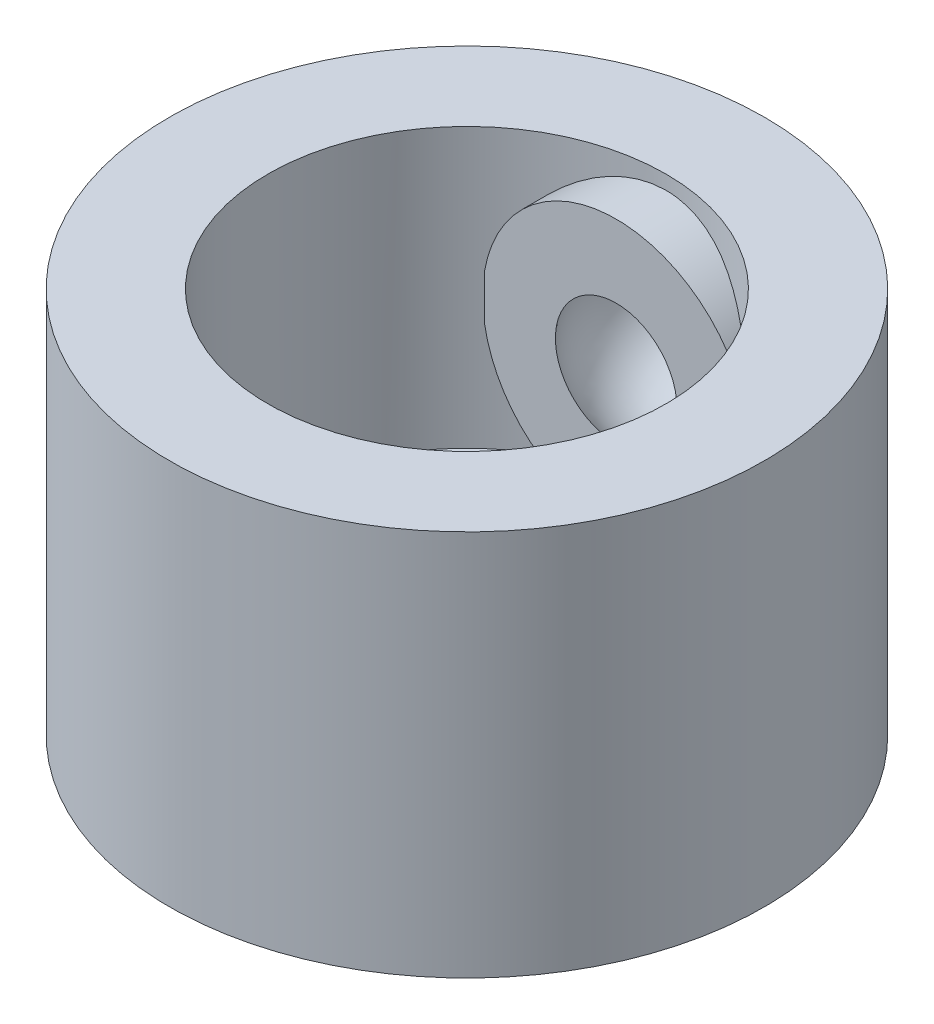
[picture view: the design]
ISO-10303-21;
HEADER;
FILE_DESCRIPTION(('STEP AP214'),'2;1');
FILE_NAME('part.step','',(''),(''),'','','');
FILE_SCHEMA(('AUTOMOTIVE_DESIGN { 1 0 10303 214 1 1 1 1 }'));
ENDSEC;
DATA;
#1=APPLICATION_CONTEXT('core data for automotive mechanical design processes');
#2=APPLICATION_PROTOCOL_DEFINITION('international standard','automotive_design',2000,#1);
#3=PRODUCT_CONTEXT('',#1,'mechanical');
#4=PRODUCT('Part','Part','',(#3));
#5=PRODUCT_RELATED_PRODUCT_CATEGORY('part','',(#4));
#6=PRODUCT_DEFINITION_FORMATION('','',#4);
#7=PRODUCT_DEFINITION_CONTEXT('part definition',#1,'design');
#8=PRODUCT_DEFINITION('design','',#6,#7);
#9=PRODUCT_DEFINITION_SHAPE('','',#8);
#10=(LENGTH_UNIT() NAMED_UNIT(*) SI_UNIT(.MILLI.,.METRE.));
#11=(NAMED_UNIT(*) PLANE_ANGLE_UNIT() SI_UNIT($,.RADIAN.));
#12=(NAMED_UNIT(*) SI_UNIT($,.STERADIAN.) SOLID_ANGLE_UNIT());
#13=UNCERTAINTY_MEASURE_WITH_UNIT(LENGTH_MEASURE(1.E-05),#10,'distance_accuracy_value','');
#14=(GEOMETRIC_REPRESENTATION_CONTEXT(3) GLOBAL_UNCERTAINTY_ASSIGNED_CONTEXT((#13)) GLOBAL_UNIT_ASSIGNED_CONTEXT((#10,
#11,#12)) REPRESENTATION_CONTEXT('',''));
#15=CARTESIAN_POINT('',(0.,0.,0.));
#16=DIRECTION('',(0.,0.,1.));
#17=DIRECTION('',(1.,0.,0.));
#18=AXIS2_PLACEMENT_3D('',#15,#16,#17);
#19=CARTESIAN_POINT('',(0.,0.,0.));
#20=DIRECTION('',(0.,-1.,0.));
#21=DIRECTION('',(0.,0.,-1.));
#22=AXIS2_PLACEMENT_3D('',#19,#20,#21);
#23=CYLINDRICAL_SURFACE('',#22,9.5);
#24=CARTESIAN_POINT('',(0.,19.1,0.));
#25=DIRECTION('',(0.,-1.,0.));
#26=DIRECTION('',(0.,0.,-1.));
#27=AXIS2_PLACEMENT_3D('',#24,#25,#26);
#28=CIRCLE('',#27,9.5);
#29=CARTESIAN_POINT('',(0.,19.1,-9.5));
#30=VERTEX_POINT('',#29);
#31=EDGE_CURVE('E335',#30,#30,#28,.T.);
#32=ORIENTED_EDGE('',*,*,#31,.F.);
#33=EDGE_LOOP('',(#32));
#34=FACE_BOUND('',#33,.T.);
#35=CARTESIAN_POINT('',(0.,18.426793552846,-9.5));
#36=CARTESIAN_POINT('',(-0.159955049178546,18.4268000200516,-9.50000608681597));
#37=CARTESIAN_POINT('',(-0.319855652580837,18.42077115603,-9.49595483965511));
#38=CARTESIAN_POINT('',(-0.638400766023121,18.3967651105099,-9.47986515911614));
#39=CARTESIAN_POINT('',(-0.797045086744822,18.3787861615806,-9.46782554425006));
#40=CARTESIAN_POINT('',(-1.11185658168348,18.3311336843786,-9.43603899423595));
#41=CARTESIAN_POINT('',(-1.26802238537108,18.3014539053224,-9.41628793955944));
#42=CARTESIAN_POINT('',(-1.57673369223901,18.2308164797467,-9.36954083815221));
#43=CARTESIAN_POINT('',(-1.7292776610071,18.1898541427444,-9.34254177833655));
#44=CARTESIAN_POINT('',(-2.02889611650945,18.0974390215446,-9.28206910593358));
#45=CARTESIAN_POINT('',(-2.17599564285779,18.0460439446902,-9.24863115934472));
#46=CARTESIAN_POINT('',(-2.46481833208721,17.9332165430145,-9.17588635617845));
#47=CARTESIAN_POINT('',(-2.60653937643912,17.8717803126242,-9.13657721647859));
#48=CARTESIAN_POINT('',(-3.02249175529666,17.6733685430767,-9.01100542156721));
#49=CARTESIAN_POINT('',(-3.28778948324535,17.5222030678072,-8.91704027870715));
#50=CARTESIAN_POINT('',(-3.81192368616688,17.1725484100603,-8.70665509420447));
#51=CARTESIAN_POINT('',(-4.06827356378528,16.9711202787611,-8.58900271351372));
#52=CARTESIAN_POINT('',(-4.54601008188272,16.5335648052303,-8.34599410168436));
#53=CARTESIAN_POINT('',(-4.76734517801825,16.2973872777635,-8.22062688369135));
#54=CARTESIAN_POINT('',(-5.08723094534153,15.8995079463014,-8.02428499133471));
#55=CARTESIAN_POINT('',(-5.19834388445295,15.748116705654,-7.95255091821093));
#56=CARTESIAN_POINT('',(-5.40733945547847,15.4352063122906,-7.81194973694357));
#57=CARTESIAN_POINT('',(-5.50521902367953,15.2736848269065,-7.74308329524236));
#58=CARTESIAN_POINT('',(-5.77765072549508,14.7749551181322,-7.54446686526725));
#59=CARTESIAN_POINT('',(-5.93164679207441,14.4227774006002,-7.42227988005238));
#60=CARTESIAN_POINT('',(-6.1400691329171,13.793123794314,-7.24999268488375));
#61=CARTESIAN_POINT('',(-6.21043874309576,13.5238532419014,-7.18926134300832));
#62=CARTESIAN_POINT('',(-6.28938905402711,13.1114611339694,-7.12002436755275));
#63=CARTESIAN_POINT('',(-6.31126834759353,12.9726402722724,-7.10059214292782));
#64=CARTESIAN_POINT('',(-6.34586023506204,12.6929523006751,-7.06969705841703));
#65=CARTESIAN_POINT('',(-6.35857278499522,12.552085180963,-7.05823423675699));
#66=CARTESIAN_POINT('',(-6.37462651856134,12.2687615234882,-7.04373851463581));
#67=CARTESIAN_POINT('',(-6.37792636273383,12.126300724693,-7.04074280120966));
#68=CARTESIAN_POINT('',(-6.37497619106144,11.8415610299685,-7.04341413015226));
#69=CARTESIAN_POINT('',(-6.36872615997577,11.6992821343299,-7.04908118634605));
#70=CARTESIAN_POINT('',(-6.34678750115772,11.4159862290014,-7.06884048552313));
#71=CARTESIAN_POINT('',(-6.33109488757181,11.2749697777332,-7.0829362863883));
#72=CARTESIAN_POINT('',(-6.29054894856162,10.9952512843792,-7.11896875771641));
#73=CARTESIAN_POINT('',(-6.26569167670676,10.8565502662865,-7.14090880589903));
#74=CARTESIAN_POINT('',(-6.18071239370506,10.4583149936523,-7.21486763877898));
#75=CARTESIAN_POINT('',(-6.10902315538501,10.2028738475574,-7.27614949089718));
#76=CARTESIAN_POINT('',(-5.93675463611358,9.70746962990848,-7.41736054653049));
#77=CARTESIAN_POINT('',(-5.83615321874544,9.46751859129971,-7.49730402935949));
#78=CARTESIAN_POINT('',(-5.63877532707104,9.06609767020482,-7.64625597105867));
#79=CARTESIAN_POINT('',(-5.54799125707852,8.90062327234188,-7.71258545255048));
#80=CARTESIAN_POINT('',(-5.35298805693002,8.57951010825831,-7.84918340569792));
#81=CARTESIAN_POINT('',(-5.24876897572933,8.42387130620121,-7.91945186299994));
#82=CARTESIAN_POINT('',(-5.02731949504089,8.12258714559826,-8.06184989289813));
#83=CARTESIAN_POINT('',(-4.91006633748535,7.97696000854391,-8.13398254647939));
#84=CARTESIAN_POINT('',(-4.66318956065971,7.69648935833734,-8.27798782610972));
#85=CARTESIAN_POINT('',(-4.53356733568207,7.56164463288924,-8.34986048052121));
#86=CARTESIAN_POINT('',(-4.26131477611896,7.30233702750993,-8.49205301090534));
#87=CARTESIAN_POINT('',(-4.1185914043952,7.17796271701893,-8.56235653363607));
#88=CARTESIAN_POINT('',(-3.82148500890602,6.94159788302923,-8.69902193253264));
#89=CARTESIAN_POINT('',(-3.66710343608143,6.82960582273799,-8.76538429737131));
#90=CARTESIAN_POINT('',(-3.34752961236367,6.61915446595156,-8.89233138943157));
#91=CARTESIAN_POINT('',(-3.18235579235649,6.52067294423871,-8.95292555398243));
#92=CARTESIAN_POINT('',(-2.84181045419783,6.33817920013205,-9.06676981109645));
#93=CARTESIAN_POINT('',(-2.66644201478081,6.25416263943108,-9.12002210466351));
#94=CARTESIAN_POINT('',(-2.34642263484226,6.11864547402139,-9.20681271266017));
#95=CARTESIAN_POINT('',(-2.20354559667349,6.0640620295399,-9.24210714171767));
#96=CARTESIAN_POINT('',(-1.9130077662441,5.9649822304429,-9.30658522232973));
#97=CARTESIAN_POINT('',(-1.765347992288,5.92048374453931,-9.33577016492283));
#98=CARTESIAN_POINT('',(-1.46614983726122,5.84211758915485,-9.38740856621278));
#99=CARTESIAN_POINT('',(-1.31461330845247,5.80824494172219,-9.40986517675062));
#100=CARTESIAN_POINT('',(-1.0085905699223,5.75155139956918,-9.44756634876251));
#101=CARTESIAN_POINT('',(-0.854104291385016,5.72873076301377,-9.46281074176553));
#102=CARTESIAN_POINT('',(-0.542824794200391,5.69441736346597,-9.48576676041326));
#103=CARTESIAN_POINT('',(-0.386025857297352,5.68296037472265,-9.49345459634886));
#104=CARTESIAN_POINT('',(-0.0718204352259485,5.67167337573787,-9.50102820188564));
#105=CARTESIAN_POINT('',(0.0855860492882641,5.67184335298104,-9.50091397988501));
#106=CARTESIAN_POINT('',(0.399766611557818,5.68380821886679,-9.49288587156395));
#107=CARTESIAN_POINT('',(0.55654064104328,5.6956039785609,-9.48497140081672));
#108=CARTESIAN_POINT('',(0.868220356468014,5.73064203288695,-9.4615337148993));
#109=CARTESIAN_POINT('',(1.02312607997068,5.75388409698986,-9.44601065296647));
#110=CARTESIAN_POINT('',(1.32249964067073,5.81008456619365,-9.40864650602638));
#111=CARTESIAN_POINT('',(1.4671094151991,5.84251725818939,-9.38714822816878));
#112=CARTESIAN_POINT('',(1.75277263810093,5.91704743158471,-9.33803159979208));
#113=CARTESIAN_POINT('',(1.89382484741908,5.95914823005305,-9.31041114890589));
#114=CARTESIAN_POINT('',(2.31039010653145,6.09926368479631,-9.21914737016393));
#115=CARTESIAN_POINT('',(2.57954474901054,6.2111359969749,-9.14707131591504));
#116=CARTESIAN_POINT('',(3.11756982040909,6.478452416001,-8.97869592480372));
#117=CARTESIAN_POINT('',(3.38450501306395,6.63677381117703,-8.88086716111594));
#118=CARTESIAN_POINT('',(3.88943647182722,6.98736062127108,-8.67161913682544));
#119=CARTESIAN_POINT('',(4.12740873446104,7.17965387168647,-8.56018875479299));
#120=CARTESIAN_POINT('',(4.47910671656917,7.50770014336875,-8.37907493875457));
#121=CARTESIAN_POINT('',(4.60325926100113,7.63358824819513,-8.31136176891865));
#122=CARTESIAN_POINT('',(4.84062795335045,7.89512373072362,-8.17539031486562));
#123=CARTESIAN_POINT('',(4.95384145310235,8.03077345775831,-8.1071319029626));
#124=CARTESIAN_POINT('',(5.1689032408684,8.31139025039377,-7.97173745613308));
#125=CARTESIAN_POINT('',(5.27074821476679,8.45636001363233,-7.90460175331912));
#126=CARTESIAN_POINT('',(5.46254982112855,8.75522236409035,-7.7732907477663));
#127=CARTESIAN_POINT('',(5.55250856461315,8.90911335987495,-7.70911492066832));
#128=CARTESIAN_POINT('',(5.70698393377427,9.20101374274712,-7.5952662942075));
#129=CARTESIAN_POINT('',(5.77328407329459,9.3378040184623,-7.54488456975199));
#130=CARTESIAN_POINT('',(5.89648305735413,9.61724513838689,-7.44899868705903));
#131=CARTESIAN_POINT('',(5.95338126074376,9.75989638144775,-7.40349486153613));
#132=CARTESIAN_POINT('',(6.05713350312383,10.0504044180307,-7.31885329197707));
#133=CARTESIAN_POINT('',(6.104002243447,10.1982532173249,-7.27970625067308));
#134=CARTESIAN_POINT('',(6.18716664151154,10.4986376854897,-7.20915731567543));
#135=CARTESIAN_POINT('',(6.22346848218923,10.6511705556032,-7.17775089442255));
#136=CARTESIAN_POINT('',(6.28035686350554,10.9370806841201,-7.12799581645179));
#137=CARTESIAN_POINT('',(6.30247703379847,11.0699364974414,-7.10840032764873));
#138=CARTESIAN_POINT('',(6.33831117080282,11.3375926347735,-7.07646743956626));
#139=CARTESIAN_POINT('',(6.35202902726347,11.4723920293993,-7.06412668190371));
#140=CARTESIAN_POINT('',(6.37084376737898,11.7430222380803,-7.04716340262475));
#141=CARTESIAN_POINT('',(6.3759443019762,11.8788525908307,-7.04253761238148));
#142=CARTESIAN_POINT('',(6.37744770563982,12.150604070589,-7.04117611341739));
#143=CARTESIAN_POINT('',(6.37385036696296,12.2865251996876,-7.04444059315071));
#144=CARTESIAN_POINT('',(6.3580301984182,12.5572498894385,-7.05872278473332));
#145=CARTESIAN_POINT('',(6.34582019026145,12.6920548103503,-7.06972897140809));
#146=CARTESIAN_POINT('',(6.3129938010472,12.9598512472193,-7.09905461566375));
#147=CARTESIAN_POINT('',(6.29237457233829,13.0928421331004,-7.11737655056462));
#148=CARTESIAN_POINT('',(6.21830463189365,13.4880400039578,-7.18241685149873));
#149=CARTESIAN_POINT('',(6.15264722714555,13.7463818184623,-7.23920425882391));
#150=CARTESIAN_POINT('',(5.96500601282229,14.3315860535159,-7.3951236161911));
#151=CARTESIAN_POINT('',(5.831551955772,14.6526657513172,-7.50205712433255));
#152=CARTESIAN_POINT('',(5.5969492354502,15.1105905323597,-7.67683255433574));
#153=CARTESIAN_POINT('',(5.51289618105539,15.2594386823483,-7.73756414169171));
#154=CARTESIAN_POINT('',(5.33377037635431,15.549049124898,-7.86210972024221));
#155=CARTESIAN_POINT('',(5.23869841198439,15.6898119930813,-7.9259234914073));
#156=CARTESIAN_POINT('',(5.03618350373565,15.9653713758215,-8.05615417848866));
#157=CARTESIAN_POINT('',(4.92854673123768,16.1000124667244,-8.12259733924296));
#158=CARTESIAN_POINT('',(4.70268570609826,16.3602115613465,-8.25541724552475));
#159=CARTESIAN_POINT('',(4.584458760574,16.4857672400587,-8.32179396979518));
#160=CARTESIAN_POINT('',(4.33776545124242,16.7272947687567,-8.45300603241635));
#161=CARTESIAN_POINT('',(4.20929814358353,16.8432657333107,-8.51784122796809));
#162=CARTESIAN_POINT('',(3.94246774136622,17.0650316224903,-8.64458030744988));
#163=CARTESIAN_POINT('',(3.80410326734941,17.1708251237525,-8.70648378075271));
#164=CARTESIAN_POINT('',(3.50321674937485,17.3818002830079,-8.83214002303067));
#165=CARTESIAN_POINT('',(3.33967248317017,17.485806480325,-8.89543136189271));
#166=CARTESIAN_POINT('',(3.00192120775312,17.679371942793,-9.01501780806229));
#167=CARTESIAN_POINT('',(2.82771964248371,17.7689385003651,-9.07131644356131));
#168=CARTESIAN_POINT('',(2.46993175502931,17.9323059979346,-9.17518705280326));
#169=CARTESIAN_POINT('',(2.2863620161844,18.0061336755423,-9.2227738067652));
#170=CARTESIAN_POINT('',(1.91113844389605,18.1369130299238,-9.30776827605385));
#171=CARTESIAN_POINT('',(1.71948893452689,18.1938736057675,-9.34518135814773));
#172=CARTESIAN_POINT('',(1.27751182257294,18.302691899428,-9.41703452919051));
#173=CARTESIAN_POINT('',(1.0252324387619,18.3490837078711,-9.44798604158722));
#174=CARTESIAN_POINT('',(0.515253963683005,18.4111250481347,-9.48946103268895));
#175=CARTESIAN_POINT('',(0.257556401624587,18.4267831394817,-9.49999019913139));
#176=CARTESIAN_POINT('',(0.,18.426793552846,-9.5));
#177=B_SPLINE_CURVE_WITH_KNOTS('',3,(#35,#36,#37,#38,#39,#40,#41,#42,#43,#44,#45,#46,#47,#48,
#49,#50,#51,#52,#53,#54,#55,#56,#57,#58,#59,#60,#61,#62,#63,#64,#65,#66,#67,#68,#69,#70,#71,#72,
#73,#74,#75,#76,#77,#78,#79,#80,#81,#82,#83,#84,#85,#86,#87,#88,#89,#90,#91,#92,#93,#94,#95,#96,
#97,#98,#99,#100,#101,#102,#103,#104,#105,#106,#107,#108,#109,#110,#111,#112,#113,#114,#115,
#116,#117,#118,#119,#120,#121,#122,#123,#124,#125,#126,#127,#128,#129,#130,#131,#132,#133,#134,
#135,#136,#137,#138,#139,#140,#141,#142,#143,#144,#145,#146,#147,#148,#149,#150,#151,#152,#153,
#154,#155,#156,#157,#158,#159,#160,#161,#162,#163,#164,#165,#166,#167,#168,#169,#170,#171,#172,
#173,#174,#175,#176),.UNSPECIFIED.,.T.,.F.,(4,2,2,2,2,2,2,2,2,2,2,2,2,2,2,2,2,2,2,2,2,2,2,2,2,2,
2,2,2,2,2,2,2,2,2,2,2,2,2,2,2,2,2,2,2,2,2,2,2,2,2,2,2,2,2,2,2,2,2,2,2,2,2,2,2,2,2,2,2,2,4),(0.,
0.479607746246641,0.95928644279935,1.43922173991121,1.91935686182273,2.39690520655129,
2.8746397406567,3.82923005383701,4.8653414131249,5.90296409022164,6.50538335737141,
7.1079418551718,8.30975029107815,9.16072070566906,9.58586396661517,10.0110092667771,
10.4380188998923,10.8650292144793,11.2922199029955,11.7195947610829,12.5332430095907,
13.3475158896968,13.9469748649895,14.5464316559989,15.1469520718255,15.7474048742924,
16.3525117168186,16.9575433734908,17.5615674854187,18.1654101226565,18.6358383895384,
19.1061671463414,19.5762752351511,20.046394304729,20.5179887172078,20.9895826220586,
21.4612118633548,21.9328316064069,22.38158569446,22.8304939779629,23.7276011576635,
24.7003056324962,25.6738108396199,26.241322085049,26.8089703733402,27.3767837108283,
27.9444960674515,28.4245075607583,28.9045517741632,29.3838874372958,29.862942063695,
30.270813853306,30.6784966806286,31.0860067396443,31.4935265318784,31.9004409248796,
32.3074932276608,33.1218666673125,34.2070549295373,34.750886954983,35.2946802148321,
35.8483807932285,36.4022225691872,36.9561154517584,37.510085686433,38.1208690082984,
38.7313428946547,39.3407712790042,39.9498775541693,40.7223474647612,41.4946022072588),.UNSPECIFIED.);
#178=CARTESIAN_POINT('',(-6.2850694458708,10.9723181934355,-7.12375617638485));
#179=VERTEX_POINT('',#178);
#180=CARTESIAN_POINT('',(-1.26530471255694,5.8,-9.41536000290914));
#181=VERTEX_POINT('',#180);
#182=EDGE_CURVE('E245',#179,#181,#177,.T.);
#183=ORIENTED_EDGE('',*,*,#182,.F.);
#184=DIRECTION('',(0.,-1.,0.));
#185=VECTOR('',#184,1.);
#186=CARTESIAN_POINT('',(-6.2850694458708,0.,-7.12375617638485));
#187=LINE('',#186,#185);
#188=CARTESIAN_POINT('',(-6.2850694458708,13.1276818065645,-7.12375617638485));
#189=VERTEX_POINT('',#188);
#190=EDGE_CURVE('E247',#189,#179,#187,.T.);
#191=ORIENTED_EDGE('',*,*,#190,.F.);
#192=CARTESIAN_POINT('',(6.2850694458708,13.1276818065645,-7.12375617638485));
#193=VERTEX_POINT('',#192);
#194=EDGE_CURVE('E246',#193,#189,#177,.T.);
#195=ORIENTED_EDGE('',*,*,#194,.F.);
#196=DIRECTION('',(0.,-1.,0.));
#197=VECTOR('',#196,1.);
#198=CARTESIAN_POINT('',(6.2850694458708,0.,-7.12375617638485));
#199=LINE('',#198,#197);
#200=CARTESIAN_POINT('',(6.2850694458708,10.9723181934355,-7.12375617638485));
#201=VERTEX_POINT('',#200);
#202=EDGE_CURVE('E287',#201,#193,#199,.F.);
#203=ORIENTED_EDGE('',*,*,#202,.F.);
#204=CARTESIAN_POINT('',(1.26530471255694,5.8,-9.41536000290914));
#205=VERTEX_POINT('',#204);
#206=EDGE_CURVE('E236',#205,#201,#177,.T.);
#207=ORIENTED_EDGE('',*,*,#206,.F.);
#208=CARTESIAN_POINT('',(0.,5.8,0.));
#209=DIRECTION('',(0.,-1.,0.));
#210=DIRECTION('',(0.,0.,-1.));
#211=AXIS2_PLACEMENT_3D('',#208,#209,#210);
#212=CIRCLE('',#211,9.5);
#213=EDGE_CURVE('E286',#205,#181,#212,.T.);
#214=ORIENTED_EDGE('',*,*,#213,.T.);
#215=EDGE_LOOP('',(#183,#191,#195,#203,#207,#214));
#216=FACE_BOUND('',#215,.T.);
#217=ADVANCED_FACE('F52',(#34,#216),#23,.F.);
#218=CARTESIAN_POINT('',(-9.5,5.8,0.));
#219=DIRECTION('',(0.,-1.,0.));
#220=DIRECTION('',(0.,0.,-1.));
#221=AXIS2_PLACEMENT_3D('',#218,#219,#220);
#222=PLANE('',#221);
#223=DIRECTION('',(-1.,0.,0.));
#224=VECTOR('',#223,1.);
#225=CARTESIAN_POINT('',(-9.5,5.8,3.175));
#226=LINE('',#225,#224);
#227=CARTESIAN_POINT('',(1.83308710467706,5.8,3.175));
#228=VERTEX_POINT('',#227);
#229=CARTESIAN_POINT('',(-1.83308710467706,5.8,3.175));
#230=VERTEX_POINT('',#229);
#231=EDGE_CURVE('E214',#228,#230,#226,.T.);
#232=ORIENTED_EDGE('',*,*,#231,.T.);
#233=DIRECTION('',(-0.5,0.,-0.866025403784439));
#234=VECTOR('',#233,1.);
#235=CARTESIAN_POINT('',(-5.12463065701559,5.8,-2.52612066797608));
#236=LINE('',#235,#234);
#237=CARTESIAN_POINT('',(-3.66617420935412,5.8,0.));
#238=VERTEX_POINT('',#237);
#239=EDGE_CURVE('E218',#230,#238,#236,.T.);
#240=ORIENTED_EDGE('',*,*,#239,.T.);
#241=DIRECTION('',(0.5,0.,-0.866025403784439));
#242=VECTOR('',#241,1.);
#243=CARTESIAN_POINT('',(-5.12463065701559,5.8,2.52612066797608));
#244=LINE('',#243,#242);
#245=CARTESIAN_POINT('',(-1.83308710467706,5.8,-3.175));
#246=VERTEX_POINT('',#245);
#247=EDGE_CURVE('E203',#238,#246,#244,.T.);
#248=ORIENTED_EDGE('',*,*,#247,.T.);
#249=DIRECTION('',(1.,0.,0.));
#250=VECTOR('',#249,1.);
#251=CARTESIAN_POINT('',(-9.5,5.8,-3.175));
#252=LINE('',#251,#250);
#253=CARTESIAN_POINT('',(1.83308710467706,5.8,-3.175));
#254=VERTEX_POINT('',#253);
#255=EDGE_CURVE('E156',#246,#254,#252,.T.);
#256=ORIENTED_EDGE('',*,*,#255,.T.);
#257=DIRECTION('',(0.5,0.,0.866025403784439));
#258=VECTOR('',#257,1.);
#259=CARTESIAN_POINT('',(0.374630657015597,5.8,-5.70112066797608));
#260=LINE('',#259,#258);
#261=CARTESIAN_POINT('',(3.66617420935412,5.8,0.));
#262=VERTEX_POINT('',#261);
#263=EDGE_CURVE('E206',#254,#262,#260,.T.);
#264=ORIENTED_EDGE('',*,*,#263,.T.);
#265=DIRECTION('',(-0.5,0.,0.866025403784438));
#266=VECTOR('',#265,1.);
#267=CARTESIAN_POINT('',(0.37463065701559,5.8,5.70112066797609));
#268=LINE('',#267,#266);
#269=EDGE_CURVE('E210',#262,#228,#268,.T.);
#270=ORIENTED_EDGE('',*,*,#269,.T.);
#271=EDGE_LOOP('',(#232,#240,#248,#256,#264,#270));
#272=FACE_BOUND('',#271,.T.);
#273=DIRECTION('',(0.,0.,-1.));
#274=VECTOR('',#273,1.);
#275=CARTESIAN_POINT('',(-1.26530471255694,5.8,-13.8));
#276=LINE('',#275,#274);
#277=CARTESIAN_POINT('',(-1.26530471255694,5.8,-7.12375617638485));
#278=VERTEX_POINT('',#277);
#279=EDGE_CURVE('E62',#181,#278,#276,.F.);
#280=ORIENTED_EDGE('',*,*,#279,.F.);
#281=ORIENTED_EDGE('',*,*,#213,.F.);
#282=DIRECTION('',(0.,0.,-1.));
#283=VECTOR('',#282,1.);
#284=CARTESIAN_POINT('',(1.26530471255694,5.8,-13.8));
#285=LINE('',#284,#283);
#286=CARTESIAN_POINT('',(1.26530471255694,5.8,-7.12375617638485));
#287=VERTEX_POINT('',#286);
#288=EDGE_CURVE('E361',#287,#205,#285,.T.);
#289=ORIENTED_EDGE('',*,*,#288,.F.);
#290=DIRECTION('',(1.,0.,0.));
#291=VECTOR('',#290,1.);
#292=CARTESIAN_POINT('',(-9.5,5.8,-7.12375617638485));
#293=LINE('',#292,#291);
#294=EDGE_CURVE('E362',#278,#287,#293,.T.);
#295=ORIENTED_EDGE('',*,*,#294,.F.);
#296=EDGE_LOOP('',(#280,#281,#289,#295));
#297=FACE_BOUND('',#296,.T.);
#298=ADVANCED_FACE('F275',(#272,#297),#222,.F.);
#299=CARTESIAN_POINT('',(0.,12.05,-14.2));
#300=DIRECTION('',(0.,0.,1.));
#301=DIRECTION('',(1.,0.,0.));
#302=AXIS2_PLACEMENT_3D('',#299,#300,#301);
#303=CYLINDRICAL_SURFACE('',#302,5.75);
#304=CARTESIAN_POINT('',(0.,17.8,-14.2));
#305=CARTESIAN_POINT('',(-0.154438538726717,17.7999990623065,-14.1999992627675));
#306=CARTESIAN_POINT('',(-0.308934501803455,17.7937693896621,-14.1974735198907));
#307=CARTESIAN_POINT('',(-0.616831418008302,17.7689073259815,-14.1874336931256));
#308=CARTESIAN_POINT('',(-0.770231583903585,17.7502667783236,-14.1799163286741));
#309=CARTESIAN_POINT('',(-1.07506274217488,17.7007194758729,-14.1600711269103));
#310=CARTESIAN_POINT('',(-1.22648886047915,17.6697867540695,-14.1477331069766));
#311=CARTESIAN_POINT('',(-1.52601131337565,17.5959529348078,-14.118567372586));
#312=CARTESIAN_POINT('',(-1.67410626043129,17.5530469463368,-14.1017378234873));
#313=CARTESIAN_POINT('',(-1.96536366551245,17.4558603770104,-14.0640971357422));
#314=CARTESIAN_POINT('',(-2.10854251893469,17.4016229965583,-14.0433011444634));
#315=CARTESIAN_POINT('',(-2.38970684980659,17.2821264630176,-13.9981993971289));
#316=CARTESIAN_POINT('',(-2.52769036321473,17.216863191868,-13.9738923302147));
#317=CARTESIAN_POINT('',(-2.79751487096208,17.075888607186,-13.9223832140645));
#318=CARTESIAN_POINT('',(-2.92936045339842,17.0001852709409,-13.8951833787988));
#319=CARTESIAN_POINT('',(-3.18632520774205,16.8388284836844,-13.8385215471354));
#320=CARTESIAN_POINT('',(-3.31144191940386,16.7531714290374,-13.8090587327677));
#321=CARTESIAN_POINT('',(-3.68623328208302,16.4742305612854,-13.715672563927));
#322=CARTESIAN_POINT('',(-3.92367604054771,16.2650555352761,-13.6490612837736));
#323=CARTESIAN_POINT('',(-4.36119743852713,15.810586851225,-13.5156377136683));
#324=CARTESIAN_POINT('',(-4.56125739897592,15.5652752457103,-13.4488253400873));
#325=CARTESIAN_POINT('',(-4.83372214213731,15.1684976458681,-13.3523408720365));
#326=CARTESIAN_POINT('',(-4.92153257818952,15.0280082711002,-13.320140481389));
#327=CARTESIAN_POINT('',(-5.08492368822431,14.7395161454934,-13.2586261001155));
#328=CARTESIAN_POINT('',(-5.16050940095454,14.5915165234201,-13.2293109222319));
#329=CARTESIAN_POINT('',(-5.29880999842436,14.2889267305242,-13.174526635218));
#330=CARTESIAN_POINT('',(-5.36152410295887,14.1343361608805,-13.1490577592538));
#331=CARTESIAN_POINT('',(-5.47343031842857,13.8197217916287,-13.1028709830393));
#332=CARTESIAN_POINT('',(-5.52262925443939,13.6597007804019,-13.082150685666));
#333=CARTESIAN_POINT('',(-5.60505949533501,13.3428156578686,-13.047038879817));
#334=CARTESIAN_POINT('',(-5.63891834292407,13.1861420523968,-13.0324011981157));
#335=CARTESIAN_POINT('',(-5.69346202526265,12.8701695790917,-13.0086655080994));
#336=CARTESIAN_POINT('',(-5.71415284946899,12.7108719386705,-12.9995649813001));
#337=CARTESIAN_POINT('',(-5.7421304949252,12.3909124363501,-12.9872311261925));
#338=CARTESIAN_POINT('',(-5.74942032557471,12.2302508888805,-12.9839964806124));
#339=CARTESIAN_POINT('',(-5.75051311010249,11.9088767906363,-12.9835126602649));
#340=CARTESIAN_POINT('',(-5.7443167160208,11.7481642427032,-12.9862631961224));
#341=CARTESIAN_POINT('',(-5.7194471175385,11.4395576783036,-12.9972338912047));
#342=CARTESIAN_POINT('',(-5.70170334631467,11.2915730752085,-13.005046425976));
#343=CARTESIAN_POINT('',(-5.65484890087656,10.9977030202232,-13.025487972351));
#344=CARTESIAN_POINT('',(-5.62573449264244,10.8518182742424,-13.0381185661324));
#345=CARTESIAN_POINT('',(-5.5564345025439,10.5632056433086,-13.0678021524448));
#346=CARTESIAN_POINT('',(-5.51625154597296,10.4204770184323,-13.0848540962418));
#347=CARTESIAN_POINT('',(-5.42515920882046,10.1389678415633,-13.1228838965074));
#348=CARTESIAN_POINT('',(-5.37424570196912,10.0001888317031,-13.1438632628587));
#349=CARTESIAN_POINT('',(-5.26098092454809,9.72465819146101,-13.1896126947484));
#350=CARTESIAN_POINT('',(-5.19841870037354,9.58800470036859,-13.2144509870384));
#351=CARTESIAN_POINT('',(-5.06302504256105,9.32038935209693,-13.266915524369));
#352=CARTESIAN_POINT('',(-4.99019013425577,9.18942944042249,-13.2945427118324));
#353=CARTESIAN_POINT('',(-4.83474626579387,8.93389717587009,-13.3518571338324));
#354=CARTESIAN_POINT('',(-4.75213595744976,8.80932570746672,-13.3815446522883));
#355=CARTESIAN_POINT('',(-4.57764349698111,8.56719191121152,-13.4422361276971));
#356=CARTESIAN_POINT('',(-4.48576085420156,8.44962995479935,-13.4732401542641));
#357=CARTESIAN_POINT('',(-4.28555225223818,8.21301789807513,-13.5383153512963));
#358=CARTESIAN_POINT('',(-4.17649951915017,8.09459488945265,-13.5724341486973));
#359=CARTESIAN_POINT('',(-3.94884927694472,7.86730293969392,-13.6404066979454));
#360=CARTESIAN_POINT('',(-3.83025457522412,7.75843120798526,-13.6742605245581));
#361=CARTESIAN_POINT('',(-3.58408968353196,7.55080663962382,-13.7408356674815));
#362=CARTESIAN_POINT('',(-3.45651428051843,7.45205976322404,-13.7735563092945));
#363=CARTESIAN_POINT('',(-3.19322936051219,7.26546137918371,-13.8369654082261));
#364=CARTESIAN_POINT('',(-3.05752312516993,7.17760551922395,-13.8676546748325));
#365=CARTESIAN_POINT('',(-2.77576852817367,7.01165686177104,-13.9268181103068));
#366=CARTESIAN_POINT('',(-2.62956183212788,6.93381074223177,-13.9552314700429));
#367=CARTESIAN_POINT('',(-2.33046941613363,6.79082950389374,-14.0082820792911));
#368=CARTESIAN_POINT('',(-2.17758642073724,6.72568925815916,-14.032920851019));
#369=CARTESIAN_POINT('',(-1.86620123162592,6.60872755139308,-14.0777138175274));
#370=CARTESIAN_POINT('',(-1.7077002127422,6.55690332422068,-14.0978689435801));
#371=CARTESIAN_POINT('',(-1.3862696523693,6.46711588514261,-14.1330954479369));
#372=CARTESIAN_POINT('',(-1.2233404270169,6.42915168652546,-14.1481671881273));
#373=CARTESIAN_POINT('',(-0.904331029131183,6.36938310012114,-14.1720219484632));
#374=CARTESIAN_POINT('',(-0.748431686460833,6.3467410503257,-14.1811298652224));
#375=CARTESIAN_POINT('',(-0.435089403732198,6.31432203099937,-14.1941988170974));
#376=CARTESIAN_POINT('',(-0.277646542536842,6.30454440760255,-14.1981601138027));
#377=CARTESIAN_POINT('',(0.0375180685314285,6.29796289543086,-14.2008246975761));
#378=CARTESIAN_POINT('',(0.19523974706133,6.30115606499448,-14.1995291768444));
#379=CARTESIAN_POINT('',(0.509756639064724,6.32047383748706,-14.1917191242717));
#380=CARTESIAN_POINT('',(0.666551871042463,6.33659818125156,-14.1852046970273));
#381=CARTESIAN_POINT('',(0.970746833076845,6.38055040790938,-14.1675606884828));
#382=CARTESIAN_POINT('',(1.11824415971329,6.40779854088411,-14.1566600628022));
#383=CARTESIAN_POINT('',(1.41034560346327,6.47363498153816,-14.1305496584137));
#384=CARTESIAN_POINT('',(1.55494875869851,6.51222699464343,-14.1153384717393));
#385=CARTESIAN_POINT('',(1.84024046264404,6.60038522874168,-14.0809855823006));
#386=CARTESIAN_POINT('',(1.98093009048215,6.64994839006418,-14.0618449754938));
#387=CARTESIAN_POINT('',(2.25764230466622,6.75965853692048,-14.0200798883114));
#388=CARTESIAN_POINT('',(2.39366309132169,6.81980955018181,-13.997454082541));
#389=CARTESIAN_POINT('',(2.66427059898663,6.95220288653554,-13.9485174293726));
#390=CARTESIAN_POINT('',(2.79868825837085,7.02475698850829,-13.9221155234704));
#391=CARTESIAN_POINT('',(3.06099620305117,7.18008773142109,-13.8668048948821));
#392=CARTESIAN_POINT('',(3.18888423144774,7.26286787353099,-13.8378953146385));
#393=CARTESIAN_POINT('',(3.43743674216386,7.43809651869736,-13.7782570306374));
#394=CARTESIAN_POINT('',(3.55809997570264,7.53054668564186,-13.7475280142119));
#395=CARTESIAN_POINT('',(3.79157205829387,7.72454964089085,-13.684976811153));
#396=CARTESIAN_POINT('',(3.90438055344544,7.826102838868,-13.6531545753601));
#397=CARTESIAN_POINT('',(4.12894821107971,8.04494007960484,-13.586993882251));
#398=CARTESIAN_POINT('',(4.24011651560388,8.16282398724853,-13.5526312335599));
#399=CARTESIAN_POINT('',(4.45215009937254,8.40760091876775,-13.4844636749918));
#400=CARTESIAN_POINT('',(4.55301855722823,8.5344911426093,-13.4506585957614));
#401=CARTESIAN_POINT('',(4.74390809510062,8.7966718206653,-13.3845264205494));
#402=CARTESIAN_POINT('',(4.83392276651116,8.9319671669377,-13.3522002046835));
#403=CARTESIAN_POINT('',(5.00236147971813,9.21005396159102,-13.2900127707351));
#404=CARTESIAN_POINT('',(5.08079038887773,9.35284222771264,-13.2601505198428));
#405=CARTESIAN_POINT('',(5.22630627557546,9.64678898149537,-13.2034803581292));
#406=CARTESIAN_POINT('',(5.29325251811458,9.79802481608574,-13.1767115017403));
#407=CARTESIAN_POINT('',(5.4140351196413,10.1062641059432,-13.127546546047));
#408=CARTESIAN_POINT('',(5.46787711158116,10.2632650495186,-13.1051485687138));
#409=CARTESIAN_POINT('',(5.56189685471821,10.5818791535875,-13.0655236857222));
#410=CARTESIAN_POINT('',(5.6020802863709,10.7434903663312,-13.0482946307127));
#411=CARTESIAN_POINT('',(5.66833490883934,11.0700841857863,-13.0196500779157));
#412=CARTESIAN_POINT('',(5.69440732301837,11.2350664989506,-13.0082340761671));
#413=CARTESIAN_POINT('',(5.73072436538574,11.5547747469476,-12.9922730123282));
#414=CARTESIAN_POINT('',(5.74199158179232,11.7093631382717,-12.9872845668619));
#415=CARTESIAN_POINT('',(5.75200260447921,12.0190219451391,-12.9828540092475));
#416=CARTESIAN_POINT('',(5.75074696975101,12.1740923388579,-12.9834116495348));
#417=CARTESIAN_POINT('',(5.73572801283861,12.4834849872,-12.9900535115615));
#418=CARTESIAN_POINT('',(5.72196627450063,12.6378073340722,-12.9961370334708));
#419=CARTESIAN_POINT('',(5.68209662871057,12.9445385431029,-13.0136178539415));
#420=CARTESIAN_POINT('',(5.65598878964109,13.0969474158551,-13.0250151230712));
#421=CARTESIAN_POINT('',(5.59305232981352,13.3924282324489,-13.0521602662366));
#422=CARTESIAN_POINT('',(5.5567176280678,13.5356241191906,-13.0677062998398));
#423=CARTESIAN_POINT('',(5.47331426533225,13.8183575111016,-13.1028572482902));
#424=CARTESIAN_POINT('',(5.42624211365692,13.9578938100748,-13.1224634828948));
#425=CARTESIAN_POINT('',(5.2694885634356,14.3697232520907,-13.186557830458));
#426=CARTESIAN_POINT('',(5.14422550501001,14.6354438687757,-13.236341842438));
#427=CARTESIAN_POINT('',(4.84750277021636,15.1580326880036,-13.3479662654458));
#428=CARTESIAN_POINT('',(4.67378071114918,15.4134880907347,-13.4103393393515));
#429=CARTESIAN_POINT('',(4.28813461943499,15.89304183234,-13.538576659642));
#430=CARTESIAN_POINT('',(4.07619855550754,16.1171302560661,-13.6044420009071));
#431=CARTESIAN_POINT('',(3.72563904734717,16.4328249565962,-13.7031293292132));
#432=CARTESIAN_POINT('',(3.59885676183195,16.5375170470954,-13.7370506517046));
#433=CARTESIAN_POINT('',(3.33651128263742,16.7358503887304,-13.8031140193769));
#434=CARTESIAN_POINT('',(3.20095132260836,16.8294956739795,-13.8352567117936));
#435=CARTESIAN_POINT('',(2.92172817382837,17.0051227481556,-13.896905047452));
#436=CARTESIAN_POINT('',(2.77805751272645,17.0870935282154,-13.9264081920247));
#437=CARTESIAN_POINT('',(2.48370556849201,17.2385531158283,-13.9819032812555));
#438=CARTESIAN_POINT('',(2.33302753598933,17.3080476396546,-14.0078968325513));
#439=CARTESIAN_POINT('',(2.02834706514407,17.4328367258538,-14.0552180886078));
#440=CARTESIAN_POINT('',(1.87444965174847,17.4883594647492,-14.0766197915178));
#441=CARTESIAN_POINT('',(1.56201155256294,17.5861899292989,-14.1147039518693));
#442=CARTESIAN_POINT('',(1.40347309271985,17.6285038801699,-14.1313886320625));
#443=CARTESIAN_POINT('',(1.08332644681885,17.6994001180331,-14.159525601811));
#444=CARTESIAN_POINT('',(0.921726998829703,17.7280167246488,-14.1709909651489));
#445=CARTESIAN_POINT('',(0.596460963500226,17.7713299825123,-14.188400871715));
#446=CARTESIAN_POINT('',(0.432796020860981,17.7860370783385,-14.194349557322));
#447=CARTESIAN_POINT('',(0.224050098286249,17.795808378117,-14.1983031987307));
#448=CARTESIAN_POINT('',(0.179258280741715,17.7973798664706,-14.1989392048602));
#449=CARTESIAN_POINT('',(0.0896459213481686,17.7994758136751,-14.1997877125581));
#450=CARTESIAN_POINT('',(0.0448253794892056,17.8000002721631,-14.2000002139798));
#451=CARTESIAN_POINT('',(0.,17.8,-14.2));
#452=B_SPLINE_CURVE_WITH_KNOTS('',3,(#304,#305,#306,#307,#308,#309,#310,#311,#312,#313,#314,
#315,#316,#317,#318,#319,#320,#321,#322,#323,#324,#325,#326,#327,#328,#329,#330,#331,#332,#333,
#334,#335,#336,#337,#338,#339,#340,#341,#342,#343,#344,#345,#346,#347,#348,#349,#350,#351,#352,
#353,#354,#355,#356,#357,#358,#359,#360,#361,#362,#363,#364,#365,#366,#367,#368,#369,#370,#371,
#372,#373,#374,#375,#376,#377,#378,#379,#380,#381,#382,#383,#384,#385,#386,#387,#388,#389,#390,
#391,#392,#393,#394,#395,#396,#397,#398,#399,#400,#401,#402,#403,#404,#405,#406,#407,#408,#409,
#410,#411,#412,#413,#414,#415,#416,#417,#418,#419,#420,#421,#422,#423,#424,#425,#426,#427,#428,
#429,#430,#431,#432,#433,#434,#435,#436,#437,#438,#439,#440,#441,#442,#443,#444,#445,#446,#447,
#448,#449,#450,#451),.UNSPECIFIED.,.T.,.F.,(4,2,2,2,2,2,2,2,2,2,2,2,2,2,2,2,2,2,2,2,2,2,2,2,2,2,
2,2,2,2,2,2,2,2,2,2,2,2,2,2,2,2,2,2,2,2,2,2,2,2,2,2,2,2,2,2,2,2,2,2,2,2,2,2,2,2,2,2,2,2,2,2,2,
4),(0.,0.463269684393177,0.926844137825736,1.3914031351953,1.85615218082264,2.31916070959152,
2.78234255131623,3.24517241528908,3.70817036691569,4.67379424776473,5.63989933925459,
6.14568641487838,6.65126448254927,7.1568731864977,7.66222608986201,8.14445909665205,
8.62647260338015,9.10837785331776,9.59025980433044,10.0374829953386,10.4848531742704,
10.9321173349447,11.379553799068,11.8360611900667,12.2927233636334,12.7494485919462,
13.206198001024,13.6993220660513,14.1923015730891,14.6855696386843,15.1786399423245,
15.6821711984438,16.1854988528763,16.688721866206,17.1919090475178,17.6646989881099,
18.1374648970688,18.6101235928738,19.0827728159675,19.5334198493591,19.984214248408,
20.4348830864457,20.885723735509,21.3502588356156,21.8149534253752,22.2797281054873,
22.7445237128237,23.2408651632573,23.7370529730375,24.2335323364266,24.7298025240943,
25.2317771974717,25.7335357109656,26.2350852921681,26.7365913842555,27.2012327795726,
27.6658534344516,28.1304152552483,28.5949745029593,29.040108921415,29.4853882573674,
30.3753163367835,31.3169829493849,32.2589465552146,32.7620943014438,33.2650577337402,
33.7684923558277,34.2716957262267,34.7660519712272,35.2601748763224,35.7530531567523,
36.2455610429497,36.3800238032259,36.5144866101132),.UNSPECIFIED.);
#453=CARTESIAN_POINT('',(0.,17.8,-14.2));
#454=VERTEX_POINT('',#453);
#455=EDGE_CURVE('E278',#454,#454,#452,.T.);
#456=ORIENTED_EDGE('',*,*,#455,.F.);
#457=EDGE_LOOP('',(#456));
#458=FACE_BOUND('',#457,.T.);
#459=CARTESIAN_POINT('',(0.,12.05,-12.4104748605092));
#460=DIRECTION('',(0.,0.,1.));
#461=DIRECTION('',(1.,0.,0.));
#462=AXIS2_PLACEMENT_3D('',#459,#460,#461);
#463=CIRCLE('',#462,5.75);
#464=CARTESIAN_POINT('',(5.75,12.05,-12.4104748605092));
#465=VERTEX_POINT('',#464);
#466=EDGE_CURVE('E367',#465,#465,#463,.F.);
#467=ORIENTED_EDGE('',*,*,#466,.F.);
#468=EDGE_LOOP('',(#467));
#469=FACE_BOUND('',#468,.T.);
#470=ADVANCED_FACE('F272',(#458,#469),#303,.F.);
#471=CARTESIAN_POINT('',(-2.5,0.,0.));
#472=DIRECTION('',(0.,1.,0.));
#473=DIRECTION('',(0.,0.,1.));
#474=AXIS2_PLACEMENT_3D('',#471,#472,#473);
#475=PLANE('',#474);
#476=DIRECTION('',(0.5,0.,-0.866025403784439));
#477=VECTOR('',#476,1.);
#478=CARTESIAN_POINT('',(-3.66617420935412,0.,0.));
#479=LINE('',#478,#477);
#480=CARTESIAN_POINT('',(-3.66617420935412,0.,0.));
#481=VERTEX_POINT('',#480);
#482=CARTESIAN_POINT('',(-1.83308710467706,0.,-3.175));
#483=VERTEX_POINT('',#482);
#484=EDGE_CURVE('E163',#481,#483,#479,.T.);
#485=ORIENTED_EDGE('',*,*,#484,.F.);
#486=DIRECTION('',(-0.5,0.,-0.866025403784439));
#487=VECTOR('',#486,1.);
#488=CARTESIAN_POINT('',(-1.83308710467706,0.,3.175));
#489=LINE('',#488,#487);
#490=CARTESIAN_POINT('',(-1.83308710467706,0.,3.175));
#491=VERTEX_POINT('',#490);
#492=EDGE_CURVE('E83',#491,#481,#489,.T.);
#493=ORIENTED_EDGE('',*,*,#492,.F.);
#494=DIRECTION('',(-1.,0.,0.));
#495=VECTOR('',#494,1.);
#496=CARTESIAN_POINT('',(1.83308710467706,0.,3.175));
#497=LINE('',#496,#495);
#498=CARTESIAN_POINT('',(1.83308710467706,0.,3.175));
#499=VERTEX_POINT('',#498);
#500=EDGE_CURVE('E184',#499,#491,#497,.T.);
#501=ORIENTED_EDGE('',*,*,#500,.F.);
#502=DIRECTION('',(-0.5,0.,0.866025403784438));
#503=VECTOR('',#502,1.);
#504=CARTESIAN_POINT('',(3.66617420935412,0.,0.));
#505=LINE('',#504,#503);
#506=CARTESIAN_POINT('',(3.66617420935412,0.,0.));
#507=VERTEX_POINT('',#506);
#508=EDGE_CURVE('E177',#507,#499,#505,.T.);
#509=ORIENTED_EDGE('',*,*,#508,.F.);
#510=DIRECTION('',(0.5,0.,0.866025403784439));
#511=VECTOR('',#510,1.);
#512=CARTESIAN_POINT('',(1.83308710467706,0.,-3.175));
#513=LINE('',#512,#511);
#514=CARTESIAN_POINT('',(1.83308710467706,0.,-3.175));
#515=VERTEX_POINT('',#514);
#516=EDGE_CURVE('E171',#515,#507,#513,.T.);
#517=ORIENTED_EDGE('',*,*,#516,.F.);
#518=DIRECTION('',(1.,0.,0.));
#519=VECTOR('',#518,1.);
#520=CARTESIAN_POINT('',(-1.83308710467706,0.,-3.175));
#521=LINE('',#520,#519);
#522=EDGE_CURVE('E153',#483,#515,#521,.T.);
#523=ORIENTED_EDGE('',*,*,#522,.F.);
#524=EDGE_LOOP('',(#485,#493,#501,#509,#517,#523));
#525=FACE_BOUND('',#524,.T.);
#526=CARTESIAN_POINT('',(0.,0.,0.));
#527=DIRECTION('',(0.,-1.,0.));
#528=DIRECTION('',(0.,0.,-1.));
#529=AXIS2_PLACEMENT_3D('',#526,#527,#528);
#530=CIRCLE('',#529,8.06);
#531=CARTESIAN_POINT('',(0.,0.,-8.06));
#532=VERTEX_POINT('',#531);
#533=EDGE_CURVE('E373',#532,#532,#530,.T.);
#534=ORIENTED_EDGE('',*,*,#533,.T.);
#535=EDGE_LOOP('',(#534));
#536=FACE_BOUND('',#535,.T.);
#537=ADVANCED_FACE('F54',(#525,#536),#475,.F.);
#538=CARTESIAN_POINT('',(0.,0.,0.));
#539=DIRECTION('',(0.,-1.,0.));
#540=DIRECTION('',(0.,0.,-1.));
#541=AXIS2_PLACEMENT_3D('',#538,#539,#540);
#542=CYLINDRICAL_SURFACE('',#541,8.06);
#543=ORIENTED_EDGE('',*,*,#533,.F.);
#544=EDGE_LOOP('',(#543));
#545=FACE_BOUND('',#544,.T.);
#546=CARTESIAN_POINT('',(0.,0.660000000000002,0.));
#547=DIRECTION('',(0.,-1.,0.));
#548=DIRECTION('',(0.,0.,-1.));
#549=AXIS2_PLACEMENT_3D('',#546,#547,#548);
#550=CIRCLE('',#549,8.06);
#551=CARTESIAN_POINT('',(0.,0.660000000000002,-8.06));
#552=VERTEX_POINT('',#551);
#553=EDGE_CURVE('E376',#552,#552,#550,.T.);
#554=ORIENTED_EDGE('',*,*,#553,.T.);
#555=EDGE_LOOP('',(#554));
#556=FACE_BOUND('',#555,.T.);
#557=ADVANCED_FACE('F581',(#545,#556),#542,.T.);
#558=CARTESIAN_POINT('',(-8.06,0.660000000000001,0.));
#559=DIRECTION('',(0.,1.,0.));
#560=DIRECTION('',(0.,0.,1.));
#561=AXIS2_PLACEMENT_3D('',#558,#559,#560);
#562=PLANE('',#561);
#563=ORIENTED_EDGE('',*,*,#553,.F.);
#564=EDGE_LOOP('',(#563));
#565=FACE_BOUND('',#564,.T.);
#566=CARTESIAN_POINT('',(0.,0.660000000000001,0.));
#567=DIRECTION('',(0.,-1.,0.));
#568=DIRECTION('',(0.,0.,-1.));
#569=AXIS2_PLACEMENT_3D('',#566,#567,#568);
#570=CIRCLE('',#569,14.2);
#571=CARTESIAN_POINT('',(0.,0.660000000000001,-14.2));
#572=VERTEX_POINT('',#571);
#573=EDGE_CURVE('E380',#572,#572,#570,.T.);
#574=ORIENTED_EDGE('',*,*,#573,.T.);
#575=EDGE_LOOP('',(#574));
#576=FACE_BOUND('',#575,.T.);
#577=ADVANCED_FACE('F293',(#565,#576),#562,.F.);
#578=CARTESIAN_POINT('',(0.,0.,0.));
#579=DIRECTION('',(0.,-1.,0.));
#580=DIRECTION('',(0.,0.,-1.));
#581=AXIS2_PLACEMENT_3D('',#578,#579,#580);
#582=CYLINDRICAL_SURFACE('',#581,14.2);
#583=CARTESIAN_POINT('',(0.,5.01255,-14.2));
#584=CARTESIAN_POINT('',(-0.0757890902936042,5.01254670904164,-14.199999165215));
#585=CARTESIAN_POINT('',(-0.151628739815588,5.00615838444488,-14.1993867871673));
#586=CARTESIAN_POINT('',(-0.301206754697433,4.98076981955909,-14.1970027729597));
#587=CARTESIAN_POINT('',(-0.374942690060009,4.96175556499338,-14.1952298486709));
#588=CARTESIAN_POINT('',(-0.518125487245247,4.91167257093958,-14.1907249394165));
#589=CARTESIAN_POINT('',(-0.587574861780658,4.88061097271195,-14.1879935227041));
#590=CARTESIAN_POINT('',(-0.720258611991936,4.80732855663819,-14.1818773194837));
#591=CARTESIAN_POINT('',(-0.783494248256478,4.76511000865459,-14.1784926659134));
#592=CARTESIAN_POINT('',(-0.902178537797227,4.67056324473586,-14.1714369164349));
#593=CARTESIAN_POINT('',(-0.957603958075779,4.61820592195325,-14.1677650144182));
#594=CARTESIAN_POINT('',(-1.05889490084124,4.50492978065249,-14.1605553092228));
#595=CARTESIAN_POINT('',(-1.1047599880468,4.44401057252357,-14.1570175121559));
#596=CARTESIAN_POINT('',(-1.18570962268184,4.31519580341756,-14.1504682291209));
#597=CARTESIAN_POINT('',(-1.22077331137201,4.24728707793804,-14.1474577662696));
#598=CARTESIAN_POINT('',(-1.27899161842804,4.10651237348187,-14.1423138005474));
#599=CARTESIAN_POINT('',(-1.30214650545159,4.0336465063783,-14.1401802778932));
#600=CARTESIAN_POINT('',(-1.33582145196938,3.8852617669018,-14.1370389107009));
#601=CARTESIAN_POINT('',(-1.34637986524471,3.80975167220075,-14.1360276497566));
#602=CARTESIAN_POINT('',(-1.3546806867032,3.65802486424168,-14.1352346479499));
#603=CARTESIAN_POINT('',(-1.35242340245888,3.58180816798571,-14.1354528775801));
#604=CARTESIAN_POINT('',(-1.33518854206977,3.43109558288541,-14.1370910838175));
#605=CARTESIAN_POINT('',(-1.32025278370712,3.35659486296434,-14.1385071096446));
#606=CARTESIAN_POINT('',(-1.27814998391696,3.21116244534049,-14.1423751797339));
#607=CARTESIAN_POINT('',(-1.25098279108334,3.14023079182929,-14.1448272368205));
#608=CARTESIAN_POINT('',(-1.18514193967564,3.00381754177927,-14.1504956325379));
#609=CARTESIAN_POINT('',(-1.14644966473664,2.93834498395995,-14.1537132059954));
#610=CARTESIAN_POINT('',(-1.05867037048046,2.81480733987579,-14.1605490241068));
#611=CARTESIAN_POINT('',(-1.00958307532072,2.75674245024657,-14.1641672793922));
#612=CARTESIAN_POINT('',(-0.902173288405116,2.64942534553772,-14.1714143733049));
#613=CARTESIAN_POINT('',(-0.843814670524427,2.60020927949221,-14.1750431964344));
#614=CARTESIAN_POINT('',(-0.719644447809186,2.51226685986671,-14.1818888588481));
#615=CARTESIAN_POINT('',(-0.653832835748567,2.47354051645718,-14.1851056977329));
#616=CARTESIAN_POINT('',(-0.516600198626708,2.40767853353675,-14.1907658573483));
#617=CARTESIAN_POINT('',(-0.445178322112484,2.38054465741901,-14.1932090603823));
#618=CARTESIAN_POINT('',(-0.298764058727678,2.3386639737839,-14.1970454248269));
#619=CARTESIAN_POINT('',(-0.223771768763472,2.32391683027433,-14.1984386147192));
#620=CARTESIAN_POINT('',(-0.0726585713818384,2.30727392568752,-14.2000143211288));
#621=CARTESIAN_POINT('',(0.00345679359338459,2.30532826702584,-14.2002015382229));
#622=CARTESIAN_POINT('',(0.154930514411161,2.31421261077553,-14.1993567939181));
#623=CARTESIAN_POINT('',(0.230288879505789,2.32504245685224,-14.1983248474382));
#624=CARTESIAN_POINT('',(0.377965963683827,2.35912900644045,-14.1951607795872));
#625=CARTESIAN_POINT('',(0.450290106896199,2.38236241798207,-14.1930307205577));
#626=CARTESIAN_POINT('',(0.590014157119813,2.44057269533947,-14.1879094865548));
#627=CARTESIAN_POINT('',(0.657413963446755,2.47554980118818,-14.1849182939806));
#628=CARTESIAN_POINT('',(0.785602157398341,2.55637884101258,-14.1783978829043));
#629=CARTESIAN_POINT('',(0.8463697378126,2.60226364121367,-14.1748670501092));
#630=CARTESIAN_POINT('',(0.959358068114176,2.70355833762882,-14.1676689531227));
#631=CARTESIAN_POINT('',(1.01157862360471,2.75896845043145,-14.1640016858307));
#632=CARTESIAN_POINT('',(1.10616317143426,2.87795824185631,-14.156929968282));
#633=CARTESIAN_POINT('',(1.14849447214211,2.94156396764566,-14.1535264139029));
#634=CARTESIAN_POINT('',(1.22187432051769,3.07501062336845,-14.1473808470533));
#635=CARTESIAN_POINT('',(1.25292301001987,3.14485147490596,-14.1446388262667));
#636=CARTESIAN_POINT('',(1.30280125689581,3.28867263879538,-14.1401322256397));
#637=CARTESIAN_POINT('',(1.32165043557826,3.36264609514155,-14.1383660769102));
#638=CARTESIAN_POINT('',(1.34665833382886,3.51272560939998,-14.1360062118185));
#639=CARTESIAN_POINT('',(1.35281738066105,3.58883161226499,-14.1354124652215));
#640=CARTESIAN_POINT('',(1.35226587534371,3.74069093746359,-14.1354652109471));
#641=CARTESIAN_POINT('',(1.34560668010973,3.8164444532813,-14.1361067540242));
#642=CARTESIAN_POINT('',(1.31971522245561,3.96575157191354,-14.1385472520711));
#643=CARTESIAN_POINT('',(1.30048294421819,4.0393051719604,-14.1403462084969));
#644=CARTESIAN_POINT('',(1.2500050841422,4.18212526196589,-14.1448974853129));
#645=CARTESIAN_POINT('',(1.21876083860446,4.2513922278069,-14.1476496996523));
#646=CARTESIAN_POINT('',(1.14515135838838,4.38370667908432,-14.1537975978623));
#647=CARTESIAN_POINT('',(1.10278621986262,4.44675421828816,-14.1571932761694));
#648=CARTESIAN_POINT('',(1.00794452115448,4.56510329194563,-14.1642617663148));
#649=CARTESIAN_POINT('',(0.955429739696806,4.62037413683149,-14.1679355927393));
#650=CARTESIAN_POINT('',(0.841853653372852,4.72134256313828,-14.1751371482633));
#651=CARTESIAN_POINT('',(0.780790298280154,4.76703784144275,-14.1786648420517));
#652=CARTESIAN_POINT('',(0.651697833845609,4.84763943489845,-14.1851849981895));
#653=CARTESIAN_POINT('',(0.583652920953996,4.88252052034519,-14.188176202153));
#654=CARTESIAN_POINT('',(0.442687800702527,4.9403160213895,-14.1932724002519));
#655=CARTESIAN_POINT('',(0.36977322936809,4.96324400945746,-14.1953783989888));
#656=CARTESIAN_POINT('',(0.247033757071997,4.99072815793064,-14.1979342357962));
#657=CARTESIAN_POINT('',(0.197994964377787,4.99890026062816,-14.1987053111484));
#658=CARTESIAN_POINT('',(0.0993113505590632,5.00981225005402,-14.1997384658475));
#659=CARTESIAN_POINT('',(0.0496665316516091,5.01255215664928,-14.200000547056));
#660=CARTESIAN_POINT('',(0.,5.01255,-14.2));
#661=B_SPLINE_CURVE_WITH_KNOTS('',3,(#583,#584,#585,#586,#587,#588,#589,#590,#591,#592,#593,
#594,#595,#596,#597,#598,#599,#600,#601,#602,#603,#604,#605,#606,#607,#608,#609,#610,#611,#612,
#613,#614,#615,#616,#617,#618,#619,#620,#621,#622,#623,#624,#625,#626,#627,#628,#629,#630,#631,
#632,#633,#634,#635,#636,#637,#638,#639,#640,#641,#642,#643,#644,#645,#646,#647,#648,#649,#650,
#651,#652,#653,#654,#655,#656,#657,#658,#659,#660),.UNSPECIFIED.,.T.,.F.,(4,2,2,2,2,2,2,2,2,2,2,
2,2,2,2,2,2,2,2,2,2,2,2,2,2,2,2,2,2,2,2,2,2,2,2,2,2,2,4),(0.,0.227185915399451,0.45462442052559,
0.681928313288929,0.909185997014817,1.13710604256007,1.365036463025,1.59340432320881,
1.8217670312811,2.04943263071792,2.27709276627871,2.504004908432,2.73091985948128,
2.95820335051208,3.18549287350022,3.41369080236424,3.64188895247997,3.87012180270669,
4.09834846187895,4.32568501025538,4.5530187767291,4.7799271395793,5.00684014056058,
5.23444572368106,5.46205648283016,5.69040934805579,5.91875934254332,6.14674114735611,
6.37471707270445,6.60178150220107,6.82884621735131,7.05588567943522,7.28292317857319,
7.51083292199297,7.73879741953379,7.96728982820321,8.19552222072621,8.3444035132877,
8.4932842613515),.UNSPECIFIED.);
#662=CARTESIAN_POINT('',(0.,5.01255,-14.2));
#663=VERTEX_POINT('',#662);
#664=EDGE_CURVE('E11',#663,#663,#661,.T.);
#665=ORIENTED_EDGE('',*,*,#664,.T.);
#666=EDGE_LOOP('',(#665));
#667=FACE_BOUND('',#666,.T.);
#668=ORIENTED_EDGE('',*,*,#455,.T.);
#669=EDGE_LOOP('',(#668));
#670=FACE_BOUND('',#669,.T.);
#671=ORIENTED_EDGE('',*,*,#573,.F.);
#672=EDGE_LOOP('',(#671));
#673=FACE_BOUND('',#672,.T.);
#674=CARTESIAN_POINT('',(0.,19.1,0.));
#675=DIRECTION('',(0.,-1.,0.));
#676=DIRECTION('',(0.,0.,-1.));
#677=AXIS2_PLACEMENT_3D('',#674,#675,#676);
#678=CIRCLE('',#677,14.2);
#679=CARTESIAN_POINT('',(0.,19.1,-14.2));
#680=VERTEX_POINT('',#679);
#681=EDGE_CURVE('E384',#680,#680,#678,.T.);
#682=ORIENTED_EDGE('',*,*,#681,.T.);
#683=EDGE_LOOP('',(#682));
#684=FACE_BOUND('',#683,.T.);
#685=ADVANCED_FACE('F289',(#667,#670,#673,#684),#582,.T.);
#686=CARTESIAN_POINT('',(-14.2,19.1,0.));
#687=DIRECTION('',(0.,-1.,0.));
#688=DIRECTION('',(0.,0.,-1.));
#689=AXIS2_PLACEMENT_3D('',#686,#687,#688);
#690=PLANE('',#689);
#691=ORIENTED_EDGE('',*,*,#681,.F.);
#692=EDGE_LOOP('',(#691));
#693=FACE_BOUND('',#692,.T.);
#694=ORIENTED_EDGE('',*,*,#31,.T.);
#695=EDGE_LOOP('',(#694));
#696=FACE_BOUND('',#695,.T.);
#697=ADVANCED_FACE('F265',(#693,#696),#690,.F.);
#698=CARTESIAN_POINT('',(2.90180181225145,12.05,-7.12375617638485));
#699=DIRECTION('',(0.,0.,-1.));
#700=DIRECTION('',(-1.,0.,0.));
#701=AXIS2_PLACEMENT_3D('',#698,#699,#700);
#702=PLANE('',#701);
#703=CARTESIAN_POINT('',(0.,12.05,-7.12375617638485));
#704=DIRECTION('',(0.,0.,-1.));
#705=DIRECTION('',(-1.,0.,0.));
#706=AXIS2_PLACEMENT_3D('',#703,#704,#705);
#707=CIRCLE('',#706,2.90180181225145);
#708=CARTESIAN_POINT('',(2.90180181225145,12.05,-7.12375617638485));
#709=VERTEX_POINT('',#708);
#710=EDGE_CURVE('E231',#709,#709,#707,.T.);
#711=ORIENTED_EDGE('',*,*,#710,.T.);
#712=EDGE_LOOP('',(#711));
#713=FACE_BOUND('',#712,.T.);
#714=CARTESIAN_POINT('',(0.,12.05,-7.12375617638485));
#715=DIRECTION('',(0.,0.,-1.));
#716=DIRECTION('',(-1.,0.,0.));
#717=AXIS2_PLACEMENT_3D('',#714,#715,#716);
#718=CIRCLE('',#717,6.37679355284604);
#719=EDGE_CURVE('E232',#201,#287,#718,.T.);
#720=ORIENTED_EDGE('',*,*,#719,.F.);
#721=ORIENTED_EDGE('',*,*,#202,.T.);
#722=EDGE_CURVE('E227',#189,#193,#718,.T.);
#723=ORIENTED_EDGE('',*,*,#722,.F.);
#724=ORIENTED_EDGE('',*,*,#190,.T.);
#725=EDGE_CURVE('E226',#278,#179,#718,.T.);
#726=ORIENTED_EDGE('',*,*,#725,.F.);
#727=ORIENTED_EDGE('',*,*,#294,.T.);
#728=EDGE_LOOP('',(#720,#721,#723,#724,#726,#727));
#729=FACE_BOUND('',#728,.T.);
#730=ADVANCED_FACE('F258',(#713,#729),#702,.F.);
#731=CARTESIAN_POINT('',(0.,12.05,-13.8));
#732=DIRECTION('',(0.,0.,-1.));
#733=DIRECTION('',(-1.,0.,0.));
#734=AXIS2_PLACEMENT_3D('',#731,#732,#733);
#735=CYLINDRICAL_SURFACE('',#734,6.37679355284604);
#736=ORIENTED_EDGE('',*,*,#722,.T.);
#737=ORIENTED_EDGE('',*,*,#194,.T.);
#738=EDGE_LOOP('',(#736,#737));
#739=FACE_BOUND('',#738,.T.);
#740=ADVANCED_FACE('F252',(#739),#735,.T.);
#741=ORIENTED_EDGE('',*,*,#725,.T.);
#742=ORIENTED_EDGE('',*,*,#182,.T.);
#743=ORIENTED_EDGE('',*,*,#279,.T.);
#744=EDGE_LOOP('',(#741,#742,#743));
#745=FACE_BOUND('',#744,.T.);
#746=ADVANCED_FACE('F257',(#745),#735,.T.);
#747=ORIENTED_EDGE('',*,*,#288,.T.);
#748=ORIENTED_EDGE('',*,*,#206,.T.);
#749=ORIENTED_EDGE('',*,*,#719,.T.);
#750=EDGE_LOOP('',(#747,#748,#749));
#751=FACE_BOUND('',#750,.T.);
#752=ADVANCED_FACE('F260',(#751),#735,.T.);
#753=CARTESIAN_POINT('',(6.37679355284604,12.05,-12.4104748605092));
#754=DIRECTION('',(0.,0.,1.));
#755=DIRECTION('',(1.,0.,0.));
#756=AXIS2_PLACEMENT_3D('',#753,#754,#755);
#757=PLANE('',#756);
#758=CARTESIAN_POINT('',(0.,12.05,-12.4104748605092));
#759=DIRECTION('',(0.,0.,-1.));
#760=DIRECTION('',(-1.,0.,0.));
#761=AXIS2_PLACEMENT_3D('',#758,#759,#760);
#762=CIRCLE('',#761,3.01638453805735);
#763=CARTESIAN_POINT('',(3.01638453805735,12.05,-12.4104748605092));
#764=VERTEX_POINT('',#763);
#765=EDGE_CURVE('E222',#764,#764,#762,.T.);
#766=ORIENTED_EDGE('',*,*,#765,.F.);
#767=EDGE_LOOP('',(#766));
#768=FACE_BOUND('',#767,.T.);
#769=ORIENTED_EDGE('',*,*,#466,.T.);
#770=EDGE_LOOP('',(#769));
#771=FACE_BOUND('',#770,.T.);
#772=ADVANCED_FACE('F261',(#768,#771),#757,.F.);
#773=CARTESIAN_POINT('',(0.,12.05,-9.83125));
#774=DIRECTION('',(0.,0.,-1.));
#775=DIRECTION('',(1.,0.,0.));
#776=AXIS2_PLACEMENT_3D('',#773,#774,#775);
#777=SPHERICAL_SURFACE('',#776,3.96875);
#778=CARTESIAN_POINT('',(2.90180181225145,12.05,-7.12375617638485));
#779=CARTESIAN_POINT('',(2.94292837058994,12.05,-7.16783275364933));
#780=CARTESIAN_POINT('',(2.98304912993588,12.05,-7.21284766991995));
#781=CARTESIAN_POINT('',(3.06119917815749,12.05,-7.30465780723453));
#782=CARTESIAN_POINT('',(3.09922846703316,12.05,-7.3514530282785));
#783=CARTESIAN_POINT('',(3.17311570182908,12.05,-7.44672740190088));
#784=CARTESIAN_POINT('',(3.20897364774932,12.05,-7.49520655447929));
#785=CARTESIAN_POINT('',(3.27844399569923,12.05,-7.59374793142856));
#786=CARTESIAN_POINT('',(3.3120563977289,12.05,-7.64381015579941));
#787=CARTESIAN_POINT('',(3.37696580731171,12.05,-7.74541379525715));
#788=CARTESIAN_POINT('',(3.40826281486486,12.05,-7.79695521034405));
#789=CARTESIAN_POINT('',(3.46847647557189,12.05,-7.90141020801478));
#790=CARTESIAN_POINT('',(3.49739312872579,12.05,-7.95432379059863));
#791=CARTESIAN_POINT('',(3.5527860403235,12.05,-8.06141327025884));
#792=CARTESIAN_POINT('',(3.57926229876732,12.05,-8.1155891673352));
#793=CARTESIAN_POINT('',(3.62971945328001,12.05,-8.22509079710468));
#794=CARTESIAN_POINT('',(3.65370034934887,12.05,-8.28041652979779));
#795=CARTESIAN_POINT('',(3.6991169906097,12.05,-8.39210296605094));
#796=CARTESIAN_POINT('',(3.72055273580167,12.05,-8.44846366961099));
#797=CARTESIAN_POINT('',(3.76083457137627,12.05,-8.56210303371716));
#798=CARTESIAN_POINT('',(3.77968066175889,12.05,-8.61938169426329));
#799=CARTESIAN_POINT('',(3.81474406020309,12.05,-8.73473805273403));
#800=CARTESIAN_POINT('',(3.83096136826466,12.05,-8.79281575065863));
#801=CARTESIAN_POINT('',(3.86073353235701,12.05,-8.90964960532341));
#802=CARTESIAN_POINT('',(3.8742883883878,12.05,-8.96840576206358));
#803=CARTESIAN_POINT('',(3.89870750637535,12.05,-9.08647454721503));
#804=CARTESIAN_POINT('',(3.90957176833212,12.05,-9.1457871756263));
#805=CARTESIAN_POINT('',(3.92858714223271,12.05,-9.2648457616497));
#806=CARTESIAN_POINT('',(3.93673825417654,12.05,-9.32459171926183));
#807=CARTESIAN_POINT('',(3.95031040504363,12.05,-9.44439292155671));
#808=CARTESIAN_POINT('',(3.95573144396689,12.05,-9.50444816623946));
#809=CARTESIAN_POINT('',(3.96383219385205,12.05,-9.62474325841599));
#810=CARTESIAN_POINT('',(3.96651190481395,12.05,-9.68498310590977));
#811=CARTESIAN_POINT('',(3.96912443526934,12.05,-9.8055223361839));
#812=CARTESIAN_POINT('',(3.96905725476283,12.05,-9.86582171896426));
#813=CARTESIAN_POINT('',(3.96617614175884,12.05,-9.98635482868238));
#814=CARTESIAN_POINT('',(3.96336220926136,12.05,-10.0465885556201));
#815=CARTESIAN_POINT('',(3.95499343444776,12.05,-10.1668652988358));
#816=CARTESIAN_POINT('',(3.94943859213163,12.05,-10.2269083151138));
#817=CARTESIAN_POINT('',(3.93559953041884,12.05,-10.3466789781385));
#818=CARTESIAN_POINT('',(3.92731531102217,12.05,-10.4064066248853));
#819=CARTESIAN_POINT('',(3.90803469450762,12.05,-10.5254225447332));
#820=CARTESIAN_POINT('',(3.89703829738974,12.05,-10.5847108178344));
#821=CARTESIAN_POINT('',(3.87235615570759,12.05,-10.7027248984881));
#822=CARTESIAN_POINT('',(3.85867041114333,12.05,-10.7614507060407));
#823=CARTESIAN_POINT('',(3.82863798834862,12.05,-10.8782179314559));
#824=CARTESIAN_POINT('',(3.81229131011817,12.05,-10.9362593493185));
#825=CARTESIAN_POINT('',(3.77697095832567,12.05,-11.0515372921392));
#826=CARTESIAN_POINT('',(3.75799728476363,12.05,-11.1087738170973));
#827=CARTESIAN_POINT('',(3.71746233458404,12.05,-11.2223231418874));
#828=CARTESIAN_POINT('',(3.69590105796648,12.05,-11.2786359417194));
#829=CARTESIAN_POINT('',(3.65023566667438,12.05,-11.3902209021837));
#830=CARTESIAN_POINT('',(3.62613155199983,12.05,-11.4454930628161));
#831=CARTESIAN_POINT('',(3.57543052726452,12.05,-11.5548819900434));
#832=CARTESIAN_POINT('',(3.54883361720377,12.05,-11.6089987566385));
#833=CARTESIAN_POINT('',(3.49320222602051,12.05,-11.7159645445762));
#834=CARTESIAN_POINT('',(3.464167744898,12.05,-11.768813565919));
#835=CARTESIAN_POINT('',(3.40372147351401,12.05,-11.8731341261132));
#836=CARTESIAN_POINT('',(3.37230968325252,12.05,-11.9246056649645));
#837=CARTESIAN_POINT('',(3.30717407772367,12.05,-12.0260644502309));
#838=CARTESIAN_POINT('',(3.27345026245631,12.05,-12.0760516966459));
#839=CARTESIAN_POINT('',(3.20376036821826,12.05,-12.1744379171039));
#840=CARTESIAN_POINT('',(3.16779428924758,12.05,-12.222836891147));
#841=CARTESIAN_POINT('',(3.09369548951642,12.05,-12.317946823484));
#842=CARTESIAN_POINT('',(3.05556276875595,12.05,-12.3646577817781));
#843=CARTESIAN_POINT('',(3.01638453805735,12.05,-12.4104748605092));
#844=B_SPLINE_CURVE_WITH_KNOTS('',3,(#778,#779,#780,#781,#782,#783,#784,#785,#786,#787,#788,
#789,#790,#791,#792,#793,#794,#795,#796,#797,#798,#799,#800,#801,#802,#803,#804,#805,#806,#807,
#808,#809,#810,#811,#812,#813,#814,#815,#816,#817,#818,#819,#820,#821,#822,#823,#824,#825,#826,
#827,#828,#829,#830,#831,#832,#833,#834,#835,#836,#837,#838,#839,#840,#841,#842,#843),
.UNSPECIFIED.,.F.,.F.,(4,2,2,2,2,2,2,2,2,2,2,2,2,2,2,2,2,2,2,2,2,2,2,2,2,2,2,2,2,2,2,2,4),(0.,
0.180835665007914,0.361671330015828,0.542506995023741,0.723342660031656,0.90417832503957,
1.08501399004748,1.2658496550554,1.44668532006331,1.62752098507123,1.80835665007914,
1.98919231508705,2.17002798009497,2.35086364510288,2.5316993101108,2.71253497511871,
2.89337064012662,3.07420630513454,3.25504197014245,3.43587763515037,3.61671330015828,
3.79754896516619,3.97838463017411,4.15922029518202,4.34005596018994,4.52089162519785,
4.70172729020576,4.88256295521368,5.06339862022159,5.24423428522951,5.42506995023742,
5.60590561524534,5.78674128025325),.UNSPECIFIED.);
#845=EDGE_CURVE('BSEAM267',#709,#764,#844,.T.);
#846=ORIENTED_EDGE('',*,*,#710,.F.);
#847=ORIENTED_EDGE('',*,*,#765,.T.);
#848=ORIENTED_EDGE('',*,*,#845,.T.);
#849=ORIENTED_EDGE('',*,*,#845,.F.);
#850=EDGE_LOOP('',(#846,#848,#847,#849));
#851=FACE_BOUND('',#850,.T.);
#852=ADVANCED_FACE('F267',(#851),#777,.F.);
#853=CARTESIAN_POINT('',(0.,3.66,-14.2));
#854=DIRECTION('',(0.,0.,-1.));
#855=DIRECTION('',(-1.,0.,0.));
#856=AXIS2_PLACEMENT_3D('',#853,#854,#855);
#857=CYLINDRICAL_SURFACE('',#856,1.35255);
#858=CARTESIAN_POINT('',(0.,3.66,-3.175));
#859=DIRECTION('',(0.,0.,-1.));
#860=DIRECTION('',(-1.,0.,0.));
#861=AXIS2_PLACEMENT_3D('',#858,#859,#860);
#862=CIRCLE('',#861,1.35255);
#863=CARTESIAN_POINT('',(-1.35255,3.66,-3.175));
#864=VERTEX_POINT('',#863);
#865=EDGE_CURVE('E56',#864,#864,#862,.F.);
#866=ORIENTED_EDGE('',*,*,#865,.T.);
#867=EDGE_LOOP('',(#866));
#868=FACE_BOUND('',#867,.T.);
#869=ORIENTED_EDGE('',*,*,#664,.F.);
#870=EDGE_LOOP('',(#869));
#871=FACE_BOUND('',#870,.T.);
#872=ADVANCED_FACE('F270',(#868,#871),#857,.F.);
#873=CARTESIAN_POINT('',(-1.83308710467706,10.,3.175));
#874=DIRECTION('',(-0.866025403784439,0.,0.5));
#875=DIRECTION('',(0.5,0.,0.866025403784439));
#876=AXIS2_PLACEMENT_3D('',#873,#874,#875);
#877=PLANE('',#876);
#878=DIRECTION('',(0.,-1.,0.));
#879=VECTOR('',#878,1.);
#880=CARTESIAN_POINT('',(-1.83308710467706,10.,3.175));
#881=LINE('',#880,#879);
#882=EDGE_CURVE('E188',#230,#491,#881,.T.);
#883=ORIENTED_EDGE('',*,*,#882,.T.);
#884=ORIENTED_EDGE('',*,*,#492,.T.);
#885=DIRECTION('',(0.,-1.,0.));
#886=VECTOR('',#885,1.);
#887=CARTESIAN_POINT('',(-3.66617420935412,10.,0.));
#888=LINE('',#887,#886);
#889=EDGE_CURVE('E160',#238,#481,#888,.T.);
#890=ORIENTED_EDGE('',*,*,#889,.F.);
#891=ORIENTED_EDGE('',*,*,#239,.F.);
#892=EDGE_LOOP('',(#883,#884,#890,#891));
#893=FACE_BOUND('',#892,.T.);
#894=ADVANCED_FACE('F304',(#893),#877,.F.);
#895=CARTESIAN_POINT('',(1.83308710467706,10.,3.175));
#896=DIRECTION('',(0.,0.,1.));
#897=DIRECTION('',(1.,0.,0.));
#898=AXIS2_PLACEMENT_3D('',#895,#896,#897);
#899=PLANE('',#898);
#900=DIRECTION('',(0.,-1.,0.));
#901=VECTOR('',#900,1.);
#902=CARTESIAN_POINT('',(1.83308710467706,10.,3.175));
#903=LINE('',#902,#901);
#904=EDGE_CURVE('E191',#228,#499,#903,.T.);
#905=ORIENTED_EDGE('',*,*,#904,.T.);
#906=ORIENTED_EDGE('',*,*,#500,.T.);
#907=ORIENTED_EDGE('',*,*,#882,.F.);
#908=ORIENTED_EDGE('',*,*,#231,.F.);
#909=EDGE_LOOP('',(#905,#906,#907,#908));
#910=FACE_BOUND('',#909,.T.);
#911=ADVANCED_FACE('F308',(#910),#899,.F.);
#912=CARTESIAN_POINT('',(3.66617420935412,10.,0.));
#913=DIRECTION('',(0.866025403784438,0.,0.5));
#914=DIRECTION('',(0.5,0.,-0.866025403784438));
#915=AXIS2_PLACEMENT_3D('',#912,#913,#914);
#916=PLANE('',#915);
#917=DIRECTION('',(0.,-1.,0.));
#918=VECTOR('',#917,1.);
#919=CARTESIAN_POINT('',(3.66617420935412,10.,0.));
#920=LINE('',#919,#918);
#921=EDGE_CURVE('E194',#262,#507,#920,.T.);
#922=ORIENTED_EDGE('',*,*,#921,.T.);
#923=ORIENTED_EDGE('',*,*,#508,.T.);
#924=ORIENTED_EDGE('',*,*,#904,.F.);
#925=ORIENTED_EDGE('',*,*,#269,.F.);
#926=EDGE_LOOP('',(#922,#923,#924,#925));
#927=FACE_BOUND('',#926,.T.);
#928=ADVANCED_FACE('F317',(#927),#916,.F.);
#929=CARTESIAN_POINT('',(1.83308710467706,10.,-3.175));
#930=DIRECTION('',(0.866025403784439,0.,-0.5));
#931=DIRECTION('',(-0.5,0.,-0.866025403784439));
#932=AXIS2_PLACEMENT_3D('',#929,#930,#931);
#933=PLANE('',#932);
#934=DIRECTION('',(0.,-1.,0.));
#935=VECTOR('',#934,1.);
#936=CARTESIAN_POINT('',(1.83308710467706,10.,-3.175));
#937=LINE('',#936,#935);
#938=EDGE_CURVE('E159',#254,#515,#937,.T.);
#939=ORIENTED_EDGE('',*,*,#938,.T.);
#940=ORIENTED_EDGE('',*,*,#516,.T.);
#941=ORIENTED_EDGE('',*,*,#921,.F.);
#942=ORIENTED_EDGE('',*,*,#263,.F.);
#943=EDGE_LOOP('',(#939,#940,#941,#942));
#944=FACE_BOUND('',#943,.T.);
#945=ADVANCED_FACE('F311',(#944),#933,.F.);
#946=CARTESIAN_POINT('',(-3.66617420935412,10.,0.));
#947=DIRECTION('',(-0.866025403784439,0.,-0.5));
#948=DIRECTION('',(-0.5,0.,0.866025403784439));
#949=AXIS2_PLACEMENT_3D('',#946,#947,#948);
#950=PLANE('',#949);
#951=ORIENTED_EDGE('',*,*,#889,.T.);
#952=ORIENTED_EDGE('',*,*,#484,.T.);
#953=DIRECTION('',(0.,-1.,0.));
#954=VECTOR('',#953,1.);
#955=CARTESIAN_POINT('',(-1.83308710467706,10.,-3.175));
#956=LINE('',#955,#954);
#957=EDGE_CURVE('E72',#246,#483,#956,.T.);
#958=ORIENTED_EDGE('',*,*,#957,.F.);
#959=ORIENTED_EDGE('',*,*,#247,.F.);
#960=EDGE_LOOP('',(#951,#952,#958,#959));
#961=FACE_BOUND('',#960,.T.);
#962=ADVANCED_FACE('F164',(#961),#950,.F.);
#963=CARTESIAN_POINT('',(-1.83308710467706,10.,-3.175));
#964=DIRECTION('',(0.,0.,-1.));
#965=DIRECTION('',(-1.,0.,0.));
#966=AXIS2_PLACEMENT_3D('',#963,#964,#965);
#967=PLANE('',#966);
#968=ORIENTED_EDGE('',*,*,#865,.F.);
#969=EDGE_LOOP('',(#968));
#970=FACE_BOUND('',#969,.T.);
#971=ORIENTED_EDGE('',*,*,#957,.T.);
#972=ORIENTED_EDGE('',*,*,#522,.T.);
#973=ORIENTED_EDGE('',*,*,#938,.F.);
#974=ORIENTED_EDGE('',*,*,#255,.F.);
#975=EDGE_LOOP('',(#971,#972,#973,#974));
#976=FACE_BOUND('',#975,.T.);
#977=ADVANCED_FACE('F150',(#970,#976),#967,.F.);
#978=CLOSED_SHELL('',(#217,#298,#470,#537,#557,#577,#685,#697,#730,#740,#746,#752,#772,#852,
#872,#894,#911,#928,#945,#962,#977));
#979=MANIFOLD_SOLID_BREP('B2',#978);
#980=ADVANCED_BREP_SHAPE_REPRESENTATION('',(#18,#979),#14);
#981=SHAPE_DEFINITION_REPRESENTATION(#9,#980);
ENDSEC;
END-ISO-10303-21;
